One B-rep face of a CAD part: STEP entity #433.
In plain terms, the planar face has unit normal (1, 0, 0).
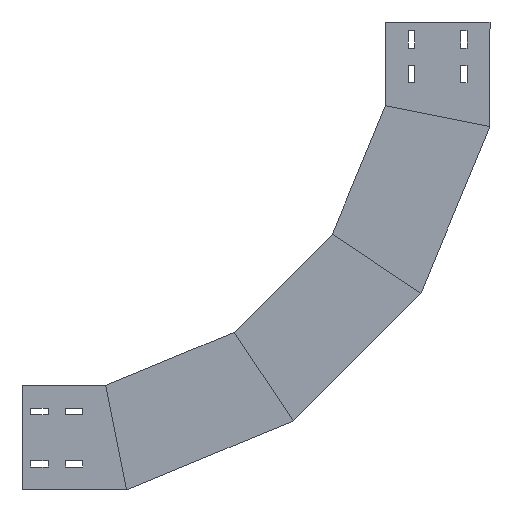
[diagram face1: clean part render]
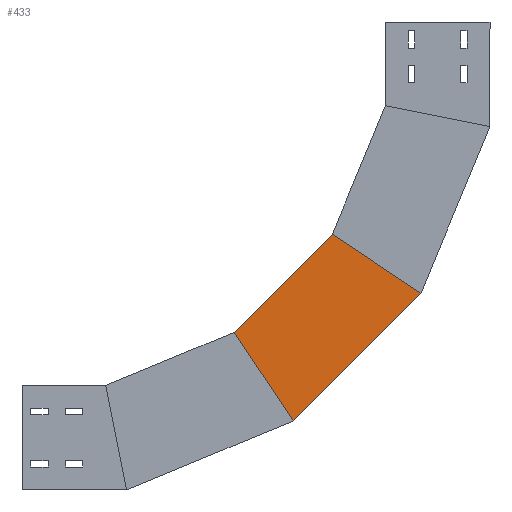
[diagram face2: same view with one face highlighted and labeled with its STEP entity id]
Its self-contained STEP definition (entity closure, numbers rounded to 3 decimals):
#275 = PLANE ( 'NONE',  #1906 ) ;
#429 = CARTESIAN_POINT ( 'NONE',  ( 0., 99.115, -389.285 ) ) ;
#433 = ADVANCED_FACE ( 'NONE', ( #2135 ), #275, .F. ) ;
#550 = LINE ( 'NONE', #1990, #1162 ) ;
#559 = CARTESIAN_POINT ( 'NONE',  ( 0., 310.328, -530.413 ) ) ;
#564 = VERTEX_POINT ( 'NONE', #2385 ) ;
#732 = DIRECTION ( 'NONE',  ( 0., 0.707, -0.707 ) ) ;
#746 = CARTESIAN_POINT ( 'NONE',  ( 0., 367.224, -445.262 ) ) ;
#747 = EDGE_CURVE ( 'NONE', #872, #2296, #1496, .T. ) ;
#765 = VERTEX_POINT ( 'NONE', #1755 ) ;
#832 = LINE ( 'NONE', #1376, #1356 ) ;
#872 = VERTEX_POINT ( 'NONE', #746 ) ;
#1055 = DIRECTION ( 'NONE',  ( 0., 0.707, -0.707 ) ) ;
#1111 = EDGE_CURVE ( 'NONE', #765, #564, #832, .T. ) ;
#1162 = VECTOR ( 'NONE', #1055, 1000. ) ;
#1209 = DIRECTION ( 'NONE',  ( 0., -0.831, -0.556 ) ) ;
#1283 = ORIENTED_EDGE ( 'NONE', *, *, #1111, .T. ) ;
#1298 = EDGE_CURVE ( 'NONE', #564, #2296, #550, .T. ) ;
#1356 = VECTOR ( 'NONE', #1209, 1000. ) ;
#1376 = CARTESIAN_POINT ( 'NONE',  ( 0., 141.128, -361.213 ) ) ;
#1485 = CARTESIAN_POINT ( 'NONE',  ( 0., 205.181, -283.219 ) ) ;
#1496 = LINE ( 'NONE', #559, #2259 ) ;
#1574 = DIRECTION ( 'NONE',  ( -1., 0., 0. ) ) ;
#1586 = EDGE_CURVE ( 'NONE', #765, #872, #2207, .T. ) ;
#1755 = CARTESIAN_POINT ( 'NONE',  ( 0., 226.279, -304.317 ) ) ;
#1830 = ORIENTED_EDGE ( 'NONE', *, *, #1586, .F. ) ;
#1861 = EDGE_LOOP ( 'NONE', ( #1830, #1283, #2163, #2335 ) ) ;
#1877 = DIRECTION ( 'NONE',  ( 0., -0.556, -0.831 ) ) ;
#1906 = AXIS2_PLACEMENT_3D ( 'NONE', #429, #1574, #2282 ) ;
#1990 = CARTESIAN_POINT ( 'NONE',  ( 0., 99.115, -389.285 ) ) ;
#2030 = VECTOR ( 'NONE', #732, 1000. ) ;
#2135 = FACE_OUTER_BOUND ( 'NONE', #1861, .T. ) ;
#2163 = ORIENTED_EDGE ( 'NONE', *, *, #1298, .T. ) ;
#2207 = LINE ( 'NONE', #1485, #2030 ) ;
#2259 = VECTOR ( 'NONE', #1877, 1000. ) ;
#2282 = DIRECTION ( 'NONE',  ( 0., 0., 1. ) ) ;
#2287 = CARTESIAN_POINT ( 'NONE',  ( 0., 282.256, -572.425 ) ) ;
#2296 = VERTEX_POINT ( 'NONE', #2287 ) ;
#2335 = ORIENTED_EDGE ( 'NONE', *, *, #747, .F. ) ;
#2385 = CARTESIAN_POINT ( 'NONE',  ( 0., 99.115, -389.285 ) ) ;
